VERSION 5.7 ;
  NOWIREEXTENSIONATPIN ON ;
  DIVIDERCHAR "/" ;
  BUSBITCHARS "[]" ;
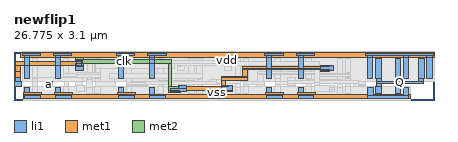
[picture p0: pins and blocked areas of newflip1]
MACRO newflip1
  CLASS BLOCK ;
  FOREIGN newflip1 ;
  ORIGIN 1.060 0.380 ;
  SIZE 26.775 BY 3.100 ;
  PIN a
    ANTENNAGATEAREA 0.253500 ;
    PORT
      LAYER li1 ;
        RECT 0.955 0.460 1.420 0.800 ;
    END
  END a
  PIN Q
    ANTENNADIFFAREA 1.395000 ;
    PORT
      LAYER li1 ;
        RECT 22.000 0.990 22.350 2.260 ;
        RECT 22.050 0.820 22.350 0.990 ;
        RECT 23.235 0.990 23.585 2.260 ;
        RECT 24.735 0.990 25.085 2.260 ;
        RECT 23.235 0.820 23.535 0.990 ;
        RECT 24.735 0.820 25.035 0.990 ;
        RECT 22.050 0.650 25.035 0.820 ;
        RECT 22.050 0.470 22.350 0.650 ;
        RECT 22.000 0.065 22.350 0.470 ;
        RECT 23.235 0.470 23.535 0.650 ;
        RECT 23.235 0.065 23.585 0.470 ;
    END
  END Q
  PIN clk
    ANTENNAGATEAREA 0.760500 ;
    PORT
      LAYER li1 ;
        RECT 2.955 1.815 3.265 2.055 ;
        RECT 18.500 1.815 19.010 1.825 ;
        RECT 2.875 1.475 3.340 1.815 ;
        RECT 18.500 1.475 19.300 1.815 ;
        RECT 18.500 1.460 19.010 1.475 ;
        RECT -0.965 0.800 -0.655 1.055 ;
        RECT -1.045 0.460 -0.580 0.800 ;
        RECT 9.455 0.380 9.920 0.525 ;
        RECT 12.660 0.520 12.880 0.525 ;
        RECT 8.915 0.185 9.920 0.380 ;
        RECT 12.190 0.255 12.880 0.520 ;
        RECT 12.415 0.185 12.880 0.255 ;
        RECT 8.915 0.165 9.500 0.185 ;
      LAYER met1 ;
        RECT 2.880 2.090 3.320 2.170 ;
        RECT -0.975 1.840 3.320 2.090 ;
        RECT -0.965 1.420 -0.660 1.840 ;
        RECT -0.305 1.825 3.320 1.840 ;
        RECT 2.880 1.785 3.320 1.825 ;
        RECT 18.480 1.750 19.045 1.835 ;
        RECT 13.485 1.630 19.045 1.750 ;
        RECT 13.480 1.570 19.045 1.630 ;
        RECT -0.965 0.790 -0.655 1.420 ;
        RECT 13.480 1.150 13.800 1.570 ;
        RECT 18.480 1.440 19.045 1.570 ;
        RECT 12.195 1.025 13.800 1.150 ;
        RECT 12.190 0.835 13.800 1.025 ;
        RECT 12.190 0.550 12.450 0.835 ;
        RECT 8.795 0.455 9.510 0.475 ;
        RECT 12.180 0.455 12.635 0.550 ;
        RECT 8.795 0.255 12.635 0.455 ;
        RECT 8.795 0.130 9.510 0.255 ;
      LAYER met2 ;
        RECT 2.865 2.185 3.360 2.305 ;
        RECT 5.375 2.185 9.000 2.190 ;
        RECT 2.865 1.970 9.000 2.185 ;
        RECT 2.865 1.960 8.580 1.970 ;
        RECT 2.865 1.955 5.375 1.960 ;
        RECT 2.865 1.785 3.360 1.955 ;
        RECT 8.795 0.500 8.995 1.970 ;
        RECT 8.795 0.130 9.585 0.500 ;
    END
  END clk
  PIN vdd
    ANTENNADIFFAREA 3.429000 ;
    PORT
      LAYER li1 ;
        RECT -0.535 2.430 0.635 2.605 ;
        RECT 1.465 2.430 2.635 2.605 ;
        RECT 5.465 2.430 6.635 2.605 ;
        RECT 7.465 2.430 8.635 2.605 ;
        RECT 14.925 2.430 16.095 2.605 ;
        RECT 16.925 2.430 18.095 2.605 ;
        RECT 21.375 2.430 25.710 2.605 ;
        RECT -0.415 0.990 -0.085 2.430 ;
        RECT 1.585 0.990 1.915 2.430 ;
        RECT 5.585 0.990 5.915 2.430 ;
        RECT 7.585 0.990 7.915 2.430 ;
        RECT 15.045 0.990 15.375 2.430 ;
        RECT 17.045 0.990 17.375 2.430 ;
        RECT 21.495 0.990 21.825 2.430 ;
        RECT 23.760 0.990 24.090 2.430 ;
        RECT 25.260 0.990 25.590 2.430 ;
      LAYER met1 ;
        RECT 9.700 2.635 11.500 2.640 ;
        RECT 18.980 2.635 20.580 2.640 ;
        RECT 22.470 2.635 24.615 2.640 ;
        RECT -0.660 2.630 12.625 2.635 ;
        RECT 14.415 2.630 25.715 2.635 ;
        RECT -0.660 2.360 25.715 2.630 ;
        RECT -0.660 2.355 12.625 2.360 ;
        RECT -0.660 2.350 9.740 2.355 ;
        RECT 11.255 2.350 12.625 2.355 ;
        RECT 14.415 2.355 25.715 2.360 ;
        RECT 14.415 2.350 22.715 2.355 ;
        RECT 22.870 2.350 24.215 2.355 ;
        RECT 24.370 2.350 25.715 2.355 ;
        RECT -0.610 2.300 0.705 2.350 ;
        RECT 1.390 2.300 2.705 2.350 ;
        RECT 5.390 2.300 6.705 2.350 ;
        RECT 7.390 2.300 8.705 2.350 ;
        RECT 14.850 2.300 16.165 2.350 ;
        RECT 16.850 2.300 18.165 2.350 ;
        RECT 18.980 2.345 21.290 2.350 ;
    END
  END vdd
  PIN vss
    ANTENNADIFFAREA 1.008000 ;
    PORT
      LAYER li1 ;
        RECT -0.410 -0.105 -0.080 0.420 ;
        RECT 1.590 -0.105 1.920 0.420 ;
        RECT 5.590 -0.105 5.920 0.420 ;
        RECT 7.590 -0.105 7.920 0.420 ;
        RECT 15.050 -0.105 15.380 0.420 ;
        RECT 17.050 -0.105 17.380 0.420 ;
        RECT 21.500 -0.105 21.830 0.420 ;
        RECT 23.755 -0.105 24.085 0.420 ;
        RECT -0.410 -0.285 0.600 -0.105 ;
        RECT 1.590 -0.285 2.600 -0.105 ;
        RECT 5.590 -0.285 6.600 -0.105 ;
        RECT 7.590 -0.285 8.600 -0.105 ;
        RECT 15.050 -0.285 16.060 -0.105 ;
        RECT 17.050 -0.285 18.060 -0.105 ;
        RECT 21.500 -0.285 24.085 -0.105 ;
      LAYER met1 ;
        RECT -0.460 -0.055 0.670 0.085 ;
        RECT 1.540 -0.055 2.670 0.085 ;
        RECT 5.540 -0.055 6.670 0.085 ;
        RECT 7.540 -0.055 9.775 -0.010 ;
        RECT 12.430 -0.055 14.370 -0.050 ;
        RECT 15.000 -0.055 16.130 0.085 ;
        RECT 17.000 -0.055 18.130 0.085 ;
        RECT 20.370 -0.055 20.715 -0.050 ;
        RECT 22.470 -0.055 23.115 -0.050 ;
        RECT -0.460 -0.300 24.195 -0.055 ;
        RECT -0.460 -0.305 0.670 -0.300 ;
        RECT 1.540 -0.305 2.670 -0.300 ;
        RECT 5.540 -0.305 6.670 -0.300 ;
        RECT 7.540 -0.305 8.670 -0.300 ;
        RECT 15.000 -0.305 16.130 -0.300 ;
        RECT 17.000 -0.305 18.130 -0.300 ;
        RECT 19.235 -0.305 22.580 -0.300 ;
        RECT 23.005 -0.305 24.135 -0.300 ;
    END
  END vss
  OBS
      LAYER nwell ;
        RECT 11.310 2.715 12.195 2.720 ;
        RECT -0.530 0.810 25.715 2.715 ;
      LAYER pwell ;
        RECT 11.375 0.485 12.210 0.490 ;
        RECT -0.470 -0.380 24.215 0.485 ;
      LAYER li1 ;
        RECT 0.090 1.075 0.440 2.260 ;
        RECT 2.090 1.300 2.430 2.260 ;
        RECT 3.595 1.300 3.915 2.265 ;
        RECT 2.090 1.130 3.915 1.300 ;
        RECT 0.090 0.990 0.690 1.075 ;
        RECT 2.090 0.990 2.430 1.130 ;
        RECT 0.140 0.820 0.690 0.990 ;
        RECT 2.140 0.900 2.430 0.990 ;
        RECT 3.595 0.900 3.915 1.130 ;
        RECT 4.090 0.990 4.440 2.260 ;
        RECT 0.140 0.470 0.440 0.820 ;
        RECT 2.140 0.470 2.440 0.900 ;
        RECT 0.090 0.065 0.440 0.470 ;
        RECT 2.090 0.065 2.440 0.470 ;
        RECT 2.940 0.530 3.265 0.795 ;
        RECT 2.940 0.185 3.420 0.530 ;
        RECT 3.590 0.420 3.915 0.900 ;
        RECT 4.140 0.780 4.440 0.990 ;
        RECT 5.030 0.800 5.345 1.080 ;
        RECT 6.090 0.990 6.440 2.260 ;
        RECT 8.090 0.990 8.440 2.260 ;
        RECT 9.430 1.815 9.630 2.035 ;
        RECT 9.375 1.475 9.840 1.815 ;
        RECT 4.955 0.780 5.420 0.800 ;
        RECT 4.140 0.500 5.420 0.780 ;
        RECT 4.140 0.470 4.440 0.500 ;
        RECT 3.590 0.005 3.920 0.420 ;
        RECT 4.090 0.065 4.440 0.470 ;
        RECT 4.955 0.460 5.420 0.500 ;
        RECT 6.140 0.755 6.440 0.990 ;
        RECT 8.140 0.875 8.440 0.990 ;
        RECT 10.090 0.875 10.415 2.265 ;
        RECT 10.590 0.990 10.940 2.260 ;
        RECT 12.370 1.815 12.620 2.110 ;
        RECT 12.335 1.475 12.800 1.815 ;
        RECT 6.955 0.795 7.420 0.800 ;
        RECT 6.955 0.755 7.610 0.795 ;
        RECT 6.140 0.615 7.610 0.755 ;
        RECT 8.140 0.695 10.415 0.875 ;
        RECT 6.140 0.530 7.420 0.615 ;
        RECT 6.140 0.470 6.440 0.530 ;
        RECT 6.090 0.065 6.440 0.470 ;
        RECT 6.955 0.460 7.420 0.530 ;
        RECT 8.140 0.470 8.440 0.695 ;
        RECT 8.090 0.065 8.440 0.470 ;
        RECT 10.090 0.420 10.415 0.695 ;
        RECT 10.640 0.470 10.940 0.990 ;
        RECT 11.410 0.935 11.825 0.955 ;
        RECT 11.410 0.930 12.040 0.935 ;
        RECT 13.050 0.930 13.375 2.265 ;
        RECT 13.550 0.990 13.900 2.260 ;
        RECT 11.410 0.695 13.375 0.930 ;
        RECT 11.410 0.615 12.040 0.695 ;
        RECT 11.410 0.610 11.825 0.615 ;
        RECT 10.090 0.020 10.420 0.420 ;
        RECT 10.590 0.065 10.940 0.470 ;
        RECT 13.050 0.420 13.375 0.695 ;
        RECT 13.600 0.780 13.900 0.990 ;
        RECT 14.495 0.800 14.805 1.025 ;
        RECT 15.550 0.990 15.900 2.260 ;
        RECT 17.550 0.990 17.900 2.260 ;
        RECT 14.415 0.780 14.880 0.800 ;
        RECT 13.600 0.600 14.880 0.780 ;
        RECT 13.600 0.470 13.900 0.600 ;
        RECT 13.050 0.010 13.380 0.420 ;
        RECT 13.550 0.065 13.900 0.470 ;
        RECT 14.415 0.460 14.880 0.600 ;
        RECT 15.600 0.785 15.900 0.990 ;
        RECT 17.600 0.950 17.900 0.990 ;
        RECT 19.550 0.950 19.875 2.255 ;
        RECT 20.050 0.990 20.400 2.255 ;
        RECT 16.430 0.800 16.790 0.925 ;
        RECT 16.415 0.785 16.880 0.800 ;
        RECT 15.600 0.605 16.880 0.785 ;
        RECT 15.600 0.470 15.900 0.605 ;
        RECT 15.550 0.065 15.900 0.470 ;
        RECT 16.415 0.460 16.880 0.605 ;
        RECT 17.600 0.695 19.875 0.950 ;
        RECT 17.600 0.470 17.900 0.695 ;
        RECT 17.550 0.065 17.900 0.470 ;
        RECT 18.915 0.445 19.380 0.525 ;
        RECT 18.650 0.265 19.380 0.445 ;
        RECT 18.915 0.185 19.380 0.265 ;
        RECT 19.550 0.420 19.875 0.695 ;
        RECT 20.100 0.470 20.400 0.990 ;
        RECT 20.945 0.800 21.255 0.805 ;
        RECT 20.600 0.780 21.330 0.800 ;
        RECT 20.590 0.600 21.330 0.780 ;
        RECT 20.600 0.520 21.330 0.600 ;
        RECT 19.550 -0.020 19.880 0.420 ;
        RECT 20.050 0.065 20.400 0.470 ;
        RECT 20.865 0.460 21.330 0.520 ;
      LAYER met1 ;
        RECT 9.425 2.165 9.645 2.170 ;
        RECT 8.905 2.160 9.645 2.165 ;
        RECT 8.900 2.120 9.645 2.160 ;
        RECT 12.370 2.125 12.675 2.130 ;
        RECT 12.350 2.120 12.675 2.125 ;
        RECT 8.900 1.975 12.675 2.120 ;
        RECT 8.900 1.960 9.150 1.975 ;
        RECT 4.130 1.640 9.150 1.960 ;
        RECT 9.385 1.830 12.675 1.975 ;
        RECT 9.385 1.775 9.645 1.830 ;
        RECT 12.350 1.810 12.675 1.830 ;
        RECT 4.130 1.635 8.340 1.640 ;
        RECT 8.900 1.635 9.150 1.640 ;
        RECT 4.155 1.380 4.475 1.635 ;
        RECT 2.960 1.270 4.475 1.380 ;
        RECT 2.940 1.085 4.475 1.270 ;
        RECT 0.430 1.070 4.475 1.085 ;
        RECT 0.430 0.775 3.305 1.070 ;
        RECT 5.010 0.975 10.940 1.330 ;
        RECT 14.485 1.290 18.265 1.415 ;
        RECT 20.075 1.290 20.370 1.360 ;
        RECT 14.485 1.225 20.370 1.290 ;
        RECT 5.010 0.960 10.835 0.975 ;
        RECT 5.010 0.805 5.365 0.960 ;
        RECT 10.630 0.950 10.835 0.960 ;
        RECT 7.395 0.795 7.625 0.820 ;
        RECT 11.410 0.795 11.825 0.955 ;
        RECT 14.485 0.805 14.815 1.225 ;
        RECT 18.110 1.135 20.370 1.225 ;
        RECT 16.355 0.895 16.890 1.045 ;
        RECT 20.075 1.040 20.370 1.135 ;
        RECT 2.875 0.530 3.305 0.775 ;
        RECT 7.350 0.615 11.825 0.795 ;
        RECT 7.395 0.585 7.625 0.615 ;
        RECT 11.410 0.610 11.825 0.615 ;
        RECT 16.355 0.650 20.910 0.895 ;
        RECT 16.355 0.555 16.890 0.650 ;
        RECT 20.570 0.510 20.910 0.650 ;
        RECT 18.545 0.220 18.985 0.510 ;
      LAYER met2 ;
        RECT 12.335 2.105 12.795 2.220 ;
        RECT 12.335 2.100 18.140 2.105 ;
        RECT 12.335 1.790 18.425 2.100 ;
        RECT 12.335 1.775 12.795 1.790 ;
        RECT 18.105 1.615 18.425 1.790 ;
        RECT 18.100 0.735 18.425 1.615 ;
        RECT 18.100 0.540 18.420 0.735 ;
        RECT 18.100 0.170 19.060 0.540 ;
  END
END newflip1
END LIBRARY

